VERSION 5.7 ;
  NOWIREEXTENSIONATPIN ON ;
  DIVIDERCHAR "/" ;
  BUSBITCHARS "[]" ;
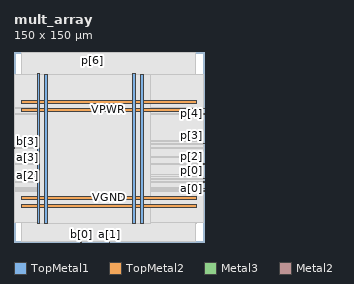
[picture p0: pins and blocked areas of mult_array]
MACRO mult_array
  CLASS BLOCK ;
  FOREIGN mult_array ;
  ORIGIN 0.000 0.000 ;
  SIZE 150.000 BY 150.000 ;
  PIN VGND
    DIRECTION INOUT ;
    USE GROUND ;
    PORT
      LAYER TopMetal1 ;
        RECT 24.460 14.490 26.660 132.520 ;
    END
    PORT
      LAYER TopMetal1 ;
        RECT 100.060 14.490 102.260 132.520 ;
    END
    PORT
      LAYER TopMetal2 ;
        RECT 5.760 33.820 144.000 36.020 ;
    END
    PORT
      LAYER TopMetal2 ;
        RECT 5.760 109.420 144.000 111.620 ;
    END
  END VGND
  PIN VPWR
    DIRECTION INOUT ;
    USE POWER ;
    PORT
      LAYER TopMetal1 ;
        RECT 18.260 14.900 20.460 132.930 ;
    END
    PORT
      LAYER TopMetal1 ;
        RECT 93.860 14.900 96.060 132.930 ;
    END
    PORT
      LAYER TopMetal2 ;
        RECT 5.760 27.620 144.000 29.820 ;
    END
    PORT
      LAYER TopMetal2 ;
        RECT 5.760 103.220 144.000 105.420 ;
    END
  END VPWR
  PIN a[0]
    DIRECTION INPUT ;
    USE SIGNAL ;
    ANTENNAGATEAREA 0.180700 ;
    PORT
      LAYER Metal3 ;
        RECT 149.600 42.220 150.000 42.620 ;
    END
  END a[0]
  PIN a[1]
    DIRECTION INPUT ;
    USE SIGNAL ;
    ANTENNAGATEAREA 0.180700 ;
    PORT
      LAYER Metal2 ;
        RECT 75.160 0.000 75.560 0.400 ;
    END
  END a[1]
  PIN a[2]
    DIRECTION INPUT ;
    USE SIGNAL ;
    ANTENNAGATEAREA 0.180700 ;
    PORT
      LAYER Metal3 ;
        RECT 0.000 52.300 0.400 52.700 ;
    END
  END a[2]
  PIN a[3]
    DIRECTION INPUT ;
    USE SIGNAL ;
    ANTENNAGATEAREA 0.180700 ;
    PORT
      LAYER Metal3 ;
        RECT 0.000 66.580 0.400 66.980 ;
    END
  END a[3]
  PIN b[0]
    DIRECTION INPUT ;
    USE SIGNAL ;
    ANTENNAGATEAREA 0.180700 ;
    PORT
      LAYER Metal2 ;
        RECT 53.080 0.000 53.480 0.400 ;
    END
  END b[0]
  PIN b[1]
    DIRECTION INPUT ;
    USE SIGNAL ;
    ANTENNAGATEAREA 0.180700 ;
    PORT
      LAYER Metal2 ;
        RECT 52.120 0.000 52.520 0.400 ;
    END
  END b[1]
  PIN b[2]
    DIRECTION INPUT ;
    USE SIGNAL ;
    ANTENNAGATEAREA 0.180700 ;
    PORT
      LAYER Metal3 ;
        RECT 0.000 74.140 0.400 74.540 ;
    END
  END b[2]
  PIN b[3]
    DIRECTION INPUT ;
    USE SIGNAL ;
    ANTENNAGATEAREA 0.180700 ;
    PORT
      LAYER Metal3 ;
        RECT 0.000 79.180 0.400 79.580 ;
    END
  END b[3]
  PIN clk
    DIRECTION INPUT ;
    USE SIGNAL ;
    ANTENNAGATEAREA 1.450800 ;
    PORT
      LAYER Metal3 ;
        RECT 149.600 39.700 150.000 40.100 ;
    END
  END clk
  PIN p[0]
    DIRECTION OUTPUT ;
    USE SIGNAL ;
    ANTENNADIFFAREA 0.708600 ;
    PORT
      LAYER Metal3 ;
        RECT 149.600 49.780 150.000 50.180 ;
    END
  END p[0]
  PIN p[1]
    DIRECTION OUTPUT ;
    USE SIGNAL ;
    ANTENNADIFFAREA 0.708600 ;
    PORT
      LAYER Metal3 ;
        RECT 149.600 47.260 150.000 47.660 ;
    END
  END p[1]
  PIN p[2]
    DIRECTION OUTPUT ;
    USE SIGNAL ;
    ANTENNADIFFAREA 0.708600 ;
    PORT
      LAYER Metal3 ;
        RECT 149.600 61.540 150.000 61.940 ;
    END
  END p[2]
  PIN p[3]
    DIRECTION OUTPUT ;
    USE SIGNAL ;
    ANTENNADIFFAREA 0.708600 ;
    PORT
      LAYER Metal3 ;
        RECT 149.600 77.500 150.000 77.900 ;
    END
  END p[3]
  PIN p[4]
    DIRECTION OUTPUT ;
    USE SIGNAL ;
    ANTENNADIFFAREA 0.708600 ;
    PORT
      LAYER Metal3 ;
        RECT 149.600 101.020 150.000 101.420 ;
    END
  END p[4]
  PIN p[5]
    DIRECTION OUTPUT ;
    USE SIGNAL ;
    ANTENNADIFFAREA 0.708600 ;
    PORT
      LAYER Metal3 ;
        RECT 149.600 105.220 150.000 105.620 ;
    END
  END p[5]
  PIN p[6]
    DIRECTION OUTPUT ;
    USE SIGNAL ;
    ANTENNADIFFAREA 0.708600 ;
    PORT
      LAYER Metal2 ;
        RECT 61.720 149.600 62.120 150.000 ;
    END
  END p[6]
  PIN p[7]
    DIRECTION OUTPUT ;
    USE SIGNAL ;
    ANTENNADIFFAREA 0.708600 ;
    PORT
      LAYER Metal2 ;
        RECT 62.680 149.600 63.080 150.000 ;
    END
  END p[7]
  PIN rst_n
    DIRECTION INPUT ;
    USE SIGNAL ;
    ANTENNAGATEAREA 0.180700 ;
    PORT
      LAYER Metal3 ;
        RECT 149.600 40.540 150.000 40.940 ;
    END
  END rst_n
  OBS
      LAYER GatPoly ;
        RECT 5.760 14.970 144.000 132.450 ;
      LAYER Metal1 ;
        RECT 5.760 14.900 144.000 132.520 ;
      LAYER Metal2 ;
        RECT 6.135 149.390 61.510 149.600 ;
        RECT 62.330 149.390 62.470 149.600 ;
        RECT 63.290 149.390 143.625 149.600 ;
        RECT 6.135 0.610 143.625 149.390 ;
        RECT 6.135 0.400 51.910 0.610 ;
        RECT 52.730 0.400 52.870 0.610 ;
        RECT 53.690 0.400 74.950 0.610 ;
        RECT 75.770 0.400 143.625 0.610 ;
      LAYER Metal3 ;
        RECT 0.400 105.830 149.600 132.400 ;
        RECT 0.400 105.010 149.390 105.830 ;
        RECT 0.400 101.630 149.600 105.010 ;
        RECT 0.400 100.810 149.390 101.630 ;
        RECT 0.400 79.790 149.600 100.810 ;
        RECT 0.610 78.970 149.600 79.790 ;
        RECT 0.400 78.110 149.600 78.970 ;
        RECT 0.400 77.290 149.390 78.110 ;
        RECT 0.400 74.750 149.600 77.290 ;
        RECT 0.610 73.930 149.600 74.750 ;
        RECT 0.400 67.190 149.600 73.930 ;
        RECT 0.610 66.370 149.600 67.190 ;
        RECT 0.400 62.150 149.600 66.370 ;
        RECT 0.400 61.330 149.390 62.150 ;
        RECT 0.400 52.910 149.600 61.330 ;
        RECT 0.610 52.090 149.600 52.910 ;
        RECT 0.400 50.390 149.600 52.090 ;
        RECT 0.400 49.570 149.390 50.390 ;
        RECT 0.400 47.870 149.600 49.570 ;
        RECT 0.400 47.050 149.390 47.870 ;
        RECT 0.400 42.830 149.600 47.050 ;
        RECT 0.400 42.010 149.390 42.830 ;
        RECT 0.400 41.150 149.600 42.010 ;
        RECT 0.400 40.330 149.390 41.150 ;
        RECT 0.400 40.310 149.600 40.330 ;
        RECT 0.400 39.490 149.390 40.310 ;
        RECT 0.400 15.020 149.600 39.490 ;
      LAYER Metal4 ;
        RECT 18.440 14.975 107.620 132.445 ;
      LAYER Metal5 ;
        RECT 18.395 14.810 102.125 132.610 ;
  END
END mult_array
END LIBRARY

